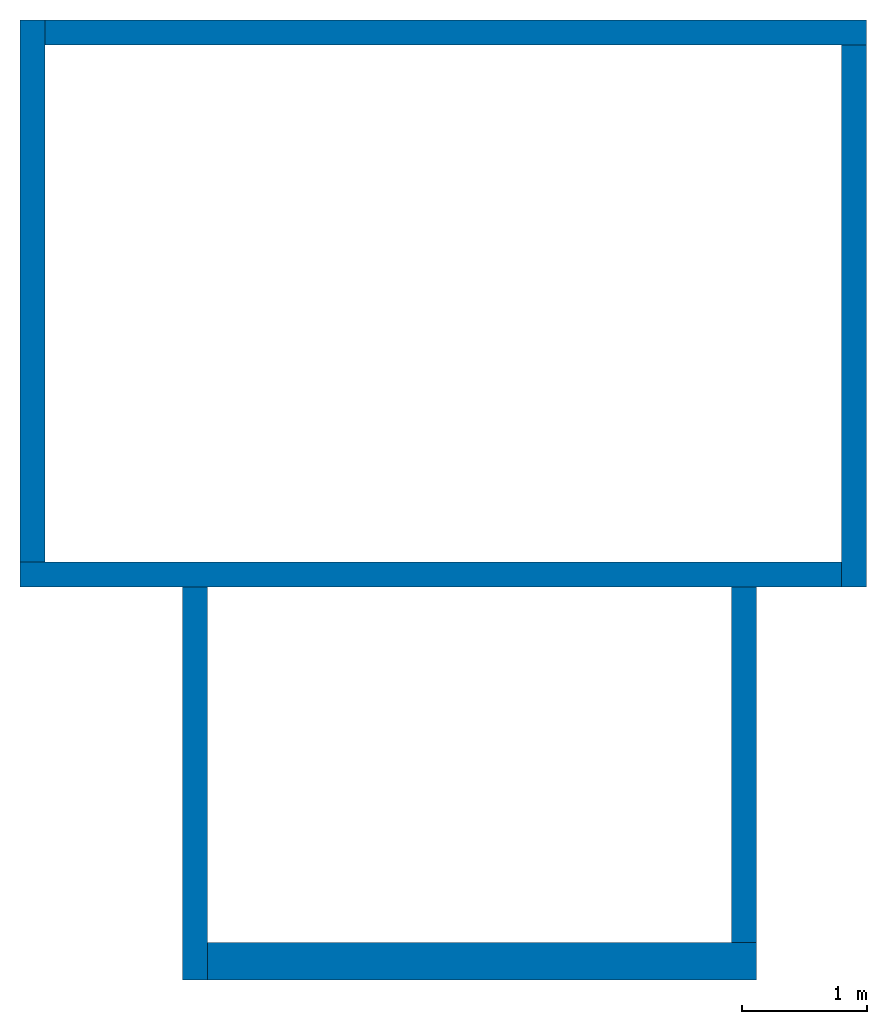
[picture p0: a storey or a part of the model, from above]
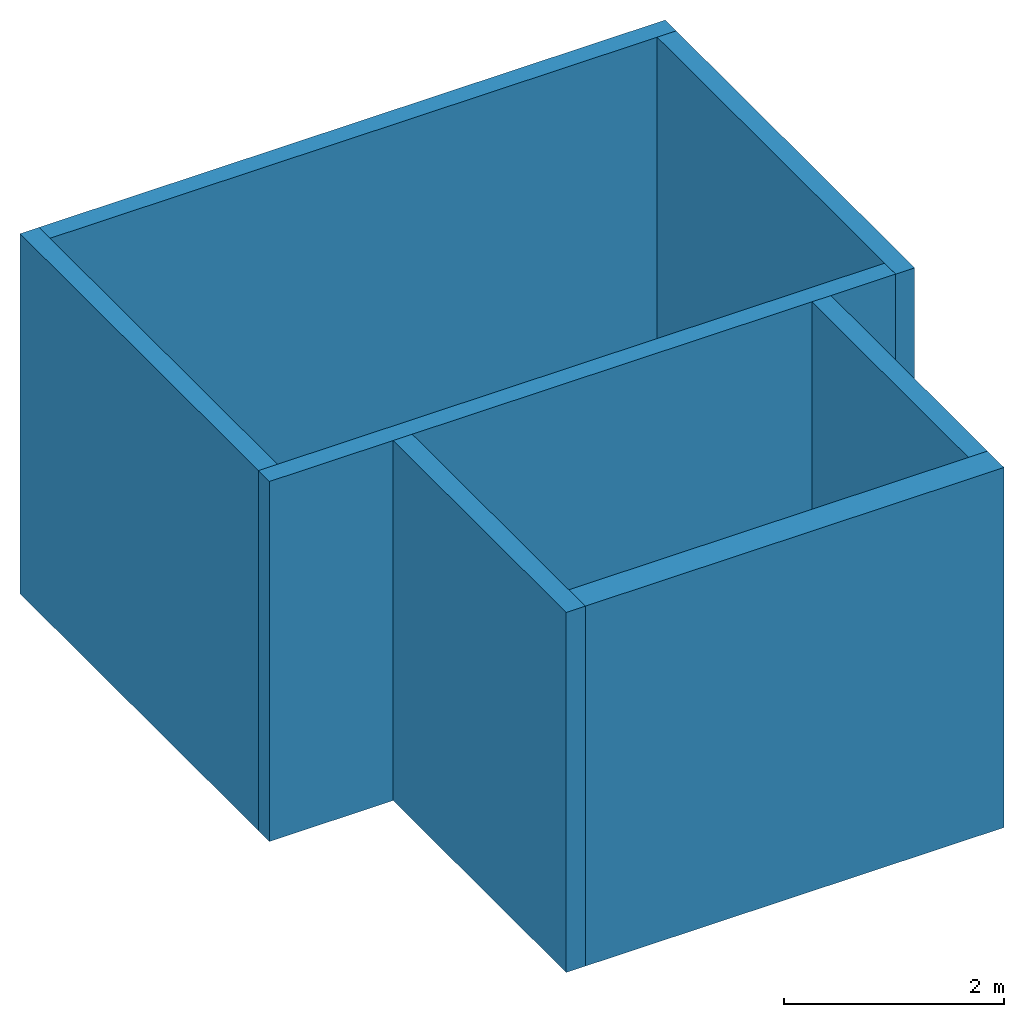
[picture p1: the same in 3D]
Properties of the parts of a building model (IFC2X3)

# File
Description: ViewDefinition [CoordinationView]
Time: 2013-11-23T08:50:42
Written by: The EXPRESS Data Manager Version 5.01.0100.02.64mod : 6 Jun 2012
Made in: 20130308_1515(x64) - Exporter 3.5.0.0 - Alternate UI 2.5.0.0
Comment: STEP Physical File produced by: The EXPRESS Data Manager Version 5.01.0100.02.64mod : 6 Jun 2012 * Module: EDMstepFileFactory/EDMstandAlone * Creation date: Sat Nov 23 08:50:42 2013 * Host: MDR_LPTP_BTO * Database: C:\Users\Martijn\AppData\Local\Temp\{8F9421B2-BBB5-4250-A466-51CCC7E0C32B}\ifc * Database version: 5507 * Database creation date: Sat Nov 23 08:50:41 2013 * Schema: IFC2X3 * Model: DataRepository.ifc * Model creation date: Sat Nov 23 08:50:42 2013 * Header model: DataRepository.ifc_HeaderModel * Header model creation date: Sat Nov 23 08:50:42 2013 * EDMuser: sdai-user * EDMgroup: sdai-group * License ID and type: 5605 : Permanent license. Expiry date: * EDMstepFileFactory options: 020000

# IfcProject
LongName: E:\MdR Advies\Google Drive\001 - Overige werkzaamheden\AU2013\files\testfile_2D Room boundaries.ifc

# IfcSite, Default
RefLatitude: 42, 24, 53, 508911; RefLongitude: -71, -15, -29, -58837; RefElevation: 0 mm

# IfcBuilding
Pset_BuildingCommon - NumberOfStoreys: 1

# IfcBuildingStorey, Level 1
LongName: Level 1; Elevation: 0 mm
Constraints - Elevation: 0 mm; Elevation Base: Project Base Point
Dimensions - Computation Height: 0 mm
Identity Data - Building Story: yes; Name: Level 1; Structural: no
Graphics - Color: 0; Line Pattern: -3000010; Line Weight: 1; Symbol at End 1 Default: no; Symbol at End 2 Default: yes

# IfcSpace (3)
In: Level 1
LongName: Room; InteriorOrExteriorSpace: INTERNAL
Constraints - Base Offset: 0 mm; Level: Level: Level 1; Limit Offset: 2438.4 mm; Upper Limit: Level: Level 1
Dimensions - Computation Height: 0 mm; Unbounded Height: 2438.4 mm
Identity Data - Name: Room
Phasing - Phase: New Construction
Name | Classification | GSA Space Areas (m2) = Area (m2) | Reference | Perimeter (mm) | Key Name | Number
1 | test_1 (ClassificationCode) | 12.834 | Room 1 | 14480 | test_1 | 1
2 | test_2 (ClassificationCode) | 11.97 | Room 2 | 14100 | test_2 | 2
3 | test_3 (ClassificationCode) | 13.5792 | Room 3 | 14840 | test_3 | 3

# IfcWallStandardCase: Basic Wall:Wall 1 (6)
In: Level 1
Type - PredefinedType: STANDARD; Material: Default Wall 200 mm
Type - Analytical Properties - Absorptance: 0.1; Roughness: 1
Type - Construction - Function: Exterior; Width: 200 mm; Wrapping at Inserts: Do not wrap
Type - Graphics - Coarse Scale Fill Color: 0
Constraints - Base Constraint: Level: Level 1; Base Extension Distance: 0 mm; Base is Attached: no; Base Offset: 0 mm; Location Line: Wall Centerline; Related to Mass: no; Room Bounding: yes; Top Extension Distance: 0 mm; Top is Attached: no; Top Offset: 0 mm; Unconnected Height: 4000 mm
Phasing - Phase Created: New Construction
Structural - Enable Analytical Model: no; Structural: no; Structural Usage: Non-bearing
Pset_WallCommon - Reference: Wall 1; LoadBearing: no; ExtendToStructure: no; IsExternal: yes
PSet_COBIE - NominalWidth: 200
Name (Basic Wall:Wall 1:...) | Area (m2) | Length (mm) = NominalLength | Volume (m3)
2277 | 26.32 | 6580 | 5.264
2278 | 17.36 | 4340 | 3.472
2279 | 26.32 | 6580 | 5.264
2280 | 17.36 | 4340 | 3.472
2354 | 12.6 | 3100 | 2.52
2422 | 11.4 | 3100 | 2.28

# IfcWallStandardCase: Basic Wall:Wall 2, Basic Wall:Wall 2:2388
In: Level 1
Type - PredefinedType: STANDARD; Material: Default Wall 100 mm, Default Wall 200 mm
Type - Analytical Properties - Absorptance: 0.1; Roughness: 1
Type - Construction - Function: Exterior; Width: 300 mm; Wrapping at Inserts: Do not wrap
Type - Graphics - Coarse Scale Fill Color: 0
Constraints - Base Constraint: Level: Level 1; Base Extension Distance: 0 mm; Base is Attached: no; Base Offset: 0 mm; Location Line: Wall Centerline; Related to Mass: no; Room Bounding: yes; Top Extension Distance: 0 mm; Top is Attached: no; Top Offset: 0 mm; Unconnected Height: 4000 mm
Dimensions - Area: 17.6 m2; Length: 4400 mm; Volume: 5.28 m3
Phasing - Phase Created: New Construction
Structural - Enable Analytical Model: no; Structural: no; Structural Usage: Non-bearing
Pset_WallCommon - Reference: Wall 2; LoadBearing: no; ExtendToStructure: no; IsExternal: yes
PSet_COBIE - NominalLength: 4400; NominalWidth: 300
